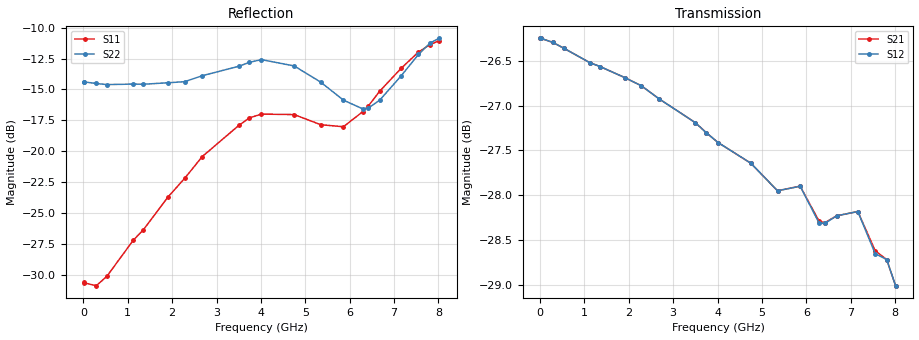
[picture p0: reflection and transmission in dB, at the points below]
! DEVICE ID: PE43712
! File Path: z:\PE43713\PE43713_CHAR_NOM_04292014\AMB\3p300\LS_ATT_25p00dB\PE43713_AMB_3p300V_3p000V_0p000V_LS_ATT_25p00dB_S2P_SN_10_A0139A.s2p
! Serial: 10
! Lot: A0139A
! Temp: 25C
! VDD: 3.300
! VSS: 0.000
! Control_Hi: 3.000
! Control_Lo: 0.000
! Attenuation Step: 25.00dB
! Port 1: RF1
! Port 2: RF2
! ThroughPath:1-2
! IDD: 0.0001454643
! ISS: -1.146e-007
#  Hz  S  RI  R  50
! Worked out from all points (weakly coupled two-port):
!   801 points, 10 MHz to 8.01 GHz, reference 50 ohm
!   highest |S21| = -26.25 dB at 20 MHz (marker M1); lowest = -29.0 dB at 8.01 GHz (marker M2)
!   lowest |S11| = -30.9 dB at 290 MHz (marker M3), VSWR 1.06, Z = 47.4 + j1.03 ohm
!   |S11| at or under -10 dB: start of sweep to end of sweep
!   |S22| runs from -16.6 to -10.9 dB; largest |S21 - S12| = 0.00018
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1e7  -0.0295 0.000802  0.0487 -0.000236  0.0487 -0.000209  -0.1911 0.00133
2e7  -0.0293 0.00139  0.0487 -0.000385  0.0487 -0.000378  -0.1908 0.00223
2.9e8  -0.0264 0.0109  0.0482 -0.0049  0.0482 -0.0049  -0.1869 0.0207
5.3e8  -0.0244 0.0194  0.0473 -0.0087  0.0473 -0.00872  -0.1826 0.0361
1.12e9  -0.0179 0.0397  0.044 -0.0171  0.044 -0.0171  -0.1712 0.0752
1.35e9  -0.0133 0.0462  0.0425 -0.02  0.0425 -0.02  -0.1645 0.0883
1.91e9  0.000823 0.0654  0.0379 -0.0266  0.0379 -0.0266  -0.1427 0.1245
2.28e9  0.0131 0.0765  0.0342 -0.0305  0.0342 -0.0305  -0.1256 0.1442
2.68e9  0.0267 0.0914  0.0298 -0.0338  0.0298 -0.0338  -0.1046 0.1731
3.5e9  0.0458 0.1186  0.0199 -0.0389  0.0199 -0.0389  -0.073 0.2083
3.74e9  0.0496 0.1271  0.0169 -0.0397  0.0169 -0.0397  -0.068 0.2187
4.01e9  0.0534 0.1309  0.0135 -0.0404  0.0135 -0.0404  -0.0641 0.226
4.75e9  0.0635 0.1256  0.00474 -0.0412  0.00478 -0.0412  -0.0411 0.2176
5.35e9  0.0802 0.0998  -0.00162 -0.04  -0.00161 -0.04  -0.0191 0.1893
5.86e9  0.1039 0.0707  -0.00732 -0.0396  -0.0073 -0.0396  0.023 0.1593
6.29e9  0.1345 0.0526  -0.0119 -0.0366  -0.0119 -0.0365  0.0722 0.1299
6.42e9  0.1444 0.0491  -0.0126 -0.0363  -0.0125 -0.0363  0.0882 0.1207
6.68e9  0.1698 0.0436  -0.0151 -0.0357  -0.0151 -0.0357  0.1209 0.1067
7.16e9  0.213 0.0398  -0.0209 -0.0329  -0.0209 -0.0329  0.1766 0.0981
7.55e9  0.2484 0.0434  -0.0237 -0.0285  -0.0236 -0.0284  0.2248 0.1013
7.81e9  0.2659 0.0481  -0.0252 -0.0266  -0.0252 -0.0266  0.2527 0.1062
8.01e9  0.275 0.0522  -0.0255 -0.0246  -0.0255 -0.0246  0.266 0.1061
